# Generated by FakeRAM 2.0
VERSION 5.7 ;
BUSBITCHARS "[]" ;
PROPERTYDEFINITIONS
  MACRO width INTEGER ;
  MACRO depth INTEGER ;
  MACRO banks INTEGER ;
END PROPERTYDEFINITIONS
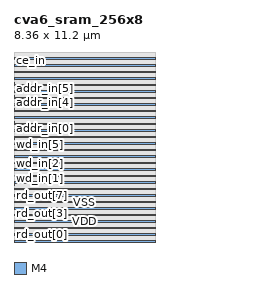
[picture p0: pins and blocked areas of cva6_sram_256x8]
MACRO cva6_sram_256x8
  PROPERTY width 8 ;
  PROPERTY depth 256 ;
  PROPERTY banks 1 ;
  FOREIGN cva6_sram_256x8 0 0 ;
  SYMMETRY X Y R90 ;
  SIZE 8.3600 BY 11.2000 ;
  CLASS BLOCK ;
  PIN rd_out[0]
    DIRECTION OUTPUT ;
    USE SIGNAL ;
    PORT
      LAYER M4 ;
      RECT 0.00000 0.04800 0.02400 0.07200 ;
    END
  END rd_out[0]
  PIN rd_out[1]
    DIRECTION OUTPUT ;
    USE SIGNAL ;
    PORT
      LAYER M4 ;
      RECT 0.00000 0.43200 0.02400 0.45600 ;
    END
  END rd_out[1]
  PIN rd_out[2]
    DIRECTION OUTPUT ;
    USE SIGNAL ;
    PORT
      LAYER M4 ;
      RECT 0.00000 0.81600 0.02400 0.84000 ;
    END
  END rd_out[2]
  PIN rd_out[3]
    DIRECTION OUTPUT ;
    USE SIGNAL ;
    PORT
      LAYER M4 ;
      RECT 0.00000 1.20000 0.02400 1.22400 ;
    END
  END rd_out[3]
  PIN rd_out[4]
    DIRECTION OUTPUT ;
    USE SIGNAL ;
    PORT
      LAYER M4 ;
      RECT 0.00000 1.58400 0.02400 1.60800 ;
    END
  END rd_out[4]
  PIN rd_out[5]
    DIRECTION OUTPUT ;
    USE SIGNAL ;
    PORT
      LAYER M4 ;
      RECT 0.00000 1.96800 0.02400 1.99200 ;
    END
  END rd_out[5]
  PIN rd_out[6]
    DIRECTION OUTPUT ;
    USE SIGNAL ;
    PORT
      LAYER M4 ;
      RECT 0.00000 2.35200 0.02400 2.37600 ;
    END
  END rd_out[6]
  PIN rd_out[7]
    DIRECTION OUTPUT ;
    USE SIGNAL ;
    PORT
      LAYER M4 ;
      RECT 0.00000 2.73600 0.02400 2.76000 ;
    END
  END rd_out[7]
  PIN wd_in[0]
    DIRECTION INPUT ;
    USE SIGNAL ;
    PORT
      LAYER M4 ;
      RECT 0.00000 3.36000 0.02400 3.38400 ;
    END
  END wd_in[0]
  PIN wd_in[1]
    DIRECTION INPUT ;
    USE SIGNAL ;
    PORT
      LAYER M4 ;
      RECT 0.00000 3.74400 0.02400 3.76800 ;
    END
  END wd_in[1]
  PIN wd_in[2]
    DIRECTION INPUT ;
    USE SIGNAL ;
    PORT
      LAYER M4 ;
      RECT 0.00000 4.12800 0.02400 4.15200 ;
    END
  END wd_in[2]
  PIN wd_in[3]
    DIRECTION INPUT ;
    USE SIGNAL ;
    PORT
      LAYER M4 ;
      RECT 0.00000 4.51200 0.02400 4.53600 ;
    END
  END wd_in[3]
  PIN wd_in[4]
    DIRECTION INPUT ;
    USE SIGNAL ;
    PORT
      LAYER M4 ;
      RECT 0.00000 4.89600 0.02400 4.92000 ;
    END
  END wd_in[4]
  PIN wd_in[5]
    DIRECTION INPUT ;
    USE SIGNAL ;
    PORT
      LAYER M4 ;
      RECT 0.00000 5.28000 0.02400 5.30400 ;
    END
  END wd_in[5]
  PIN wd_in[6]
    DIRECTION INPUT ;
    USE SIGNAL ;
    PORT
      LAYER M4 ;
      RECT 0.00000 5.66400 0.02400 5.68800 ;
    END
  END wd_in[6]
  PIN wd_in[7]
    DIRECTION INPUT ;
    USE SIGNAL ;
    PORT
      LAYER M4 ;
      RECT 0.00000 6.04800 0.02400 6.07200 ;
    END
  END wd_in[7]
  PIN addr_in[0]
    DIRECTION INPUT ;
    USE SIGNAL ;
    PORT
      LAYER M4 ;
      RECT 0.00000 6.67200 0.02400 6.69600 ;
    END
  END addr_in[0]
  PIN addr_in[1]
    DIRECTION INPUT ;
    USE SIGNAL ;
    PORT
      LAYER M4 ;
      RECT 0.00000 7.05600 0.02400 7.08000 ;
    END
  END addr_in[1]
  PIN addr_in[2]
    DIRECTION INPUT ;
    USE SIGNAL ;
    PORT
      LAYER M4 ;
      RECT 0.00000 7.44000 0.02400 7.46400 ;
    END
  END addr_in[2]
  PIN addr_in[3]
    DIRECTION INPUT ;
    USE SIGNAL ;
    PORT
      LAYER M4 ;
      RECT 0.00000 7.82400 0.02400 7.84800 ;
    END
  END addr_in[3]
  PIN addr_in[4]
    DIRECTION INPUT ;
    USE SIGNAL ;
    PORT
      LAYER M4 ;
      RECT 0.00000 8.20800 0.02400 8.23200 ;
    END
  END addr_in[4]
  PIN addr_in[5]
    DIRECTION INPUT ;
    USE SIGNAL ;
    PORT
      LAYER M4 ;
      RECT 0.00000 8.59200 0.02400 8.61600 ;
    END
  END addr_in[5]
  PIN addr_in[6]
    DIRECTION INPUT ;
    USE SIGNAL ;
    PORT
      LAYER M4 ;
      RECT 0.00000 8.97600 0.02400 9.00000 ;
    END
  END addr_in[6]
  PIN addr_in[7]
    DIRECTION INPUT ;
    USE SIGNAL ;
    PORT
      LAYER M4 ;
      RECT 0.00000 9.36000 0.02400 9.38400 ;
    END
  END addr_in[7]
  PIN we_in
    DIRECTION INPUT ;
    USE SIGNAL ;
    PORT
      LAYER M4 ;
      RECT 0.00000 9.98400 0.02400 10.00800 ;
    END
  END we_in
  PIN clk
    DIRECTION INPUT ;
    USE SIGNAL ;
    PORT
      LAYER M4 ;
      RECT 0.00000 10.36800 0.02400 10.39200 ;
    END
  END clk
  PIN ce_in
    DIRECTION INPUT ;
    USE SIGNAL ;
    PORT
      LAYER M4 ;
      RECT 0.00000 10.75200 0.02400 10.77600 ;
    END
  END ce_in
  PIN VDD
    DIRECTION INOUT ;
    USE POWER ;
    PORT
      LAYER M4 ;
      RECT 0.04800 0.38400 8.31200 0.48000 ;
      RECT 0.04800 1.15200 8.31200 1.24800 ;
      RECT 0.04800 1.92000 8.31200 2.01600 ;
      RECT 0.04800 2.68800 8.31200 2.78400 ;
      RECT 0.04800 3.45600 8.31200 3.55200 ;
      RECT 0.04800 4.22400 8.31200 4.32000 ;
      RECT 0.04800 4.99200 8.31200 5.08800 ;
      RECT 0.04800 5.76000 8.31200 5.85600 ;
      RECT 0.04800 6.52800 8.31200 6.62400 ;
      RECT 0.04800 7.29600 8.31200 7.39200 ;
      RECT 0.04800 8.06400 8.31200 8.16000 ;
      RECT 0.04800 8.83200 8.31200 8.92800 ;
      RECT 0.04800 9.60000 8.31200 9.69600 ;
      RECT 0.04800 10.36800 8.31200 10.46400 ;
    END
  END VDD
  PIN VSS
    DIRECTION INOUT ;
    USE GROUND ;
    PORT
      LAYER M4 ;
      RECT 0.04800 0.00000 8.31200 0.09600 ;
      RECT 0.04800 0.76800 8.31200 0.86400 ;
      RECT 0.04800 1.53600 8.31200 1.63200 ;
      RECT 0.04800 2.30400 8.31200 2.40000 ;
      RECT 0.04800 3.07200 8.31200 3.16800 ;
      RECT 0.04800 3.84000 8.31200 3.93600 ;
      RECT 0.04800 4.60800 8.31200 4.70400 ;
      RECT 0.04800 5.37600 8.31200 5.47200 ;
      RECT 0.04800 6.14400 8.31200 6.24000 ;
      RECT 0.04800 6.91200 8.31200 7.00800 ;
      RECT 0.04800 7.68000 8.31200 7.77600 ;
      RECT 0.04800 8.44800 8.31200 8.54400 ;
      RECT 0.04800 9.21600 8.31200 9.31200 ;
      RECT 0.04800 9.98400 8.31200 10.08000 ;
      RECT 0.04800 10.75200 8.31200 10.84800 ;
    END
  END VSS
  OBS
    LAYER M1 ;
    RECT 0 0 8.36000 11.20000 ;
    LAYER M2 ;
    RECT 0 0 8.36000 11.20000 ;
    LAYER M3 ;
    RECT 0 0 8.36000 11.20000 ;
    LAYER M4 ;
    RECT 0 0 8.36000 11.20000 ;
  END
END cva6_sram_256x8

END LIBRARY
